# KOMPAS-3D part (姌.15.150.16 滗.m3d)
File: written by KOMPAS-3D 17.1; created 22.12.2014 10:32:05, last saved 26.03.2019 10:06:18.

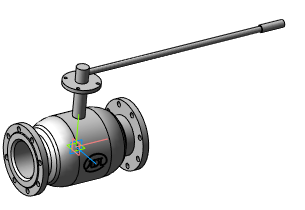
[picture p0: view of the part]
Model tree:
1. Операция без истории:6  (labels: Сталь 20  ГОСТ 1050-88)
